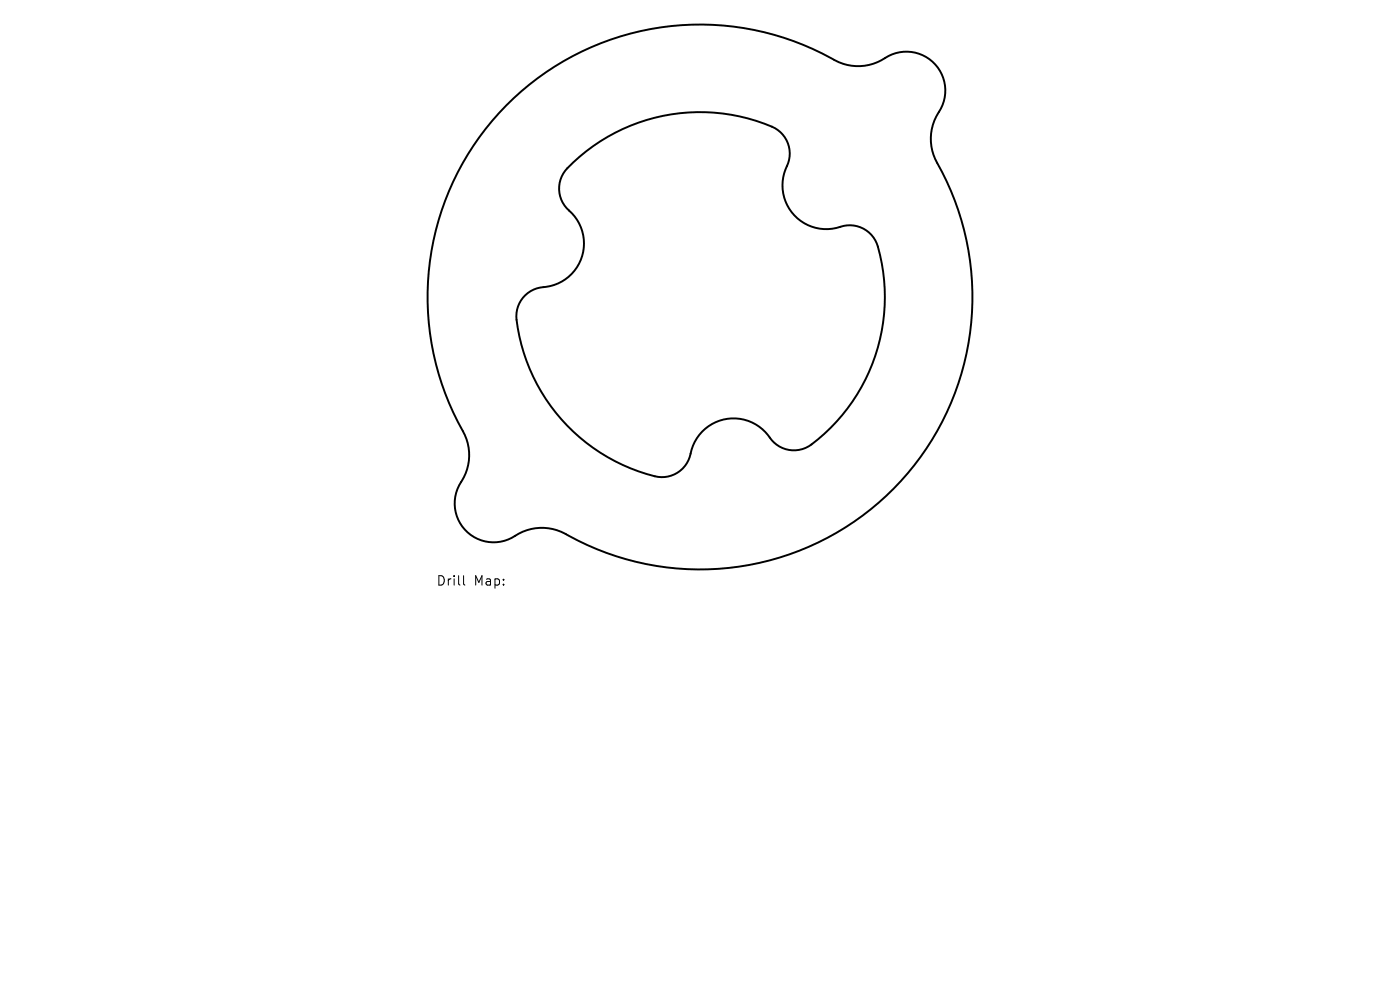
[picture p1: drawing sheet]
<svg xmlns="http://www.w3.org/2000/svg" width="297mm" height="210mm" viewBox="0 0 297 210" stroke-linecap="round" stroke-linejoin="round" font-family="sans-serif">
<defs><g id="words">
<g font-size="2.8">
<text x="92.5" y="124.5">Drill</text>
<text x="100.5" y="124.5">Map:</text>
</g>
</g></defs>
<path d="M107.4 22.4a58 58 0 0 1 70.6-9.2 10.6 10.6 0 0 0 10.5-1.3 8.3 8.3 0 0 1 10 1.9 8.3 8.3 0 0 1 .6 10.2 10.3 10.3 0 0 0-.3 10.5 57.8 57.8 0 0 1-9.9 69.8 57.8 57.8 0 0 1-69.9 8.5 10.6 10.6 0 0 0-10.5 1.3 8.3 8.3 0 0 1-10-1.9 8.3 8.3 0 0 1-.6-10.2 10.3 10.3 0 0 0 .3-10.5 57.8 57.8 0 0 1 9.2-69.1zM120.4 35.7a39.1 39.1 0 0 1 44-8.5 6.3 6.3 0 0 1 2.3 8.6 9.3 9.3 0 0 0 2.1 10.2 9.3 9.3 0 0 0 10.2 1.9 6.2 6.2 0 0 1 7.2 4.4 39.1 39.1 0 0 1-14.6 42.4 6.3 6.3 0 0 1-8.7-2.4 9.3 9.3 0 0 0-9.8-3.2 9.3 9.3 0 0 0-6.8 7.8 6.2 6.2 0 0 1-7.4 4.1 39.1 39.1 0 0 1-29.4-33.9 6.3 6.3 0 0 1 6.4-6.3 9.3 9.3 0 0 0 7.7-6.9 9.3 9.3 0 0 0-3.4-9.7 6.2 6.2 0 0 1 .2-8.5z" fill="none" stroke="#000" stroke-width=".41"/>
<path d="M98.3 122.1v1.7l.3 .3" fill="none" stroke="#000" stroke-width=".21"/>
<use href="#words"/>
</svg>
